VERSION 5.7 ;
  NOWIREEXTENSIONATPIN ON ;
  DIVIDERCHAR "/" ;
  BUSBITCHARS "[]" ;
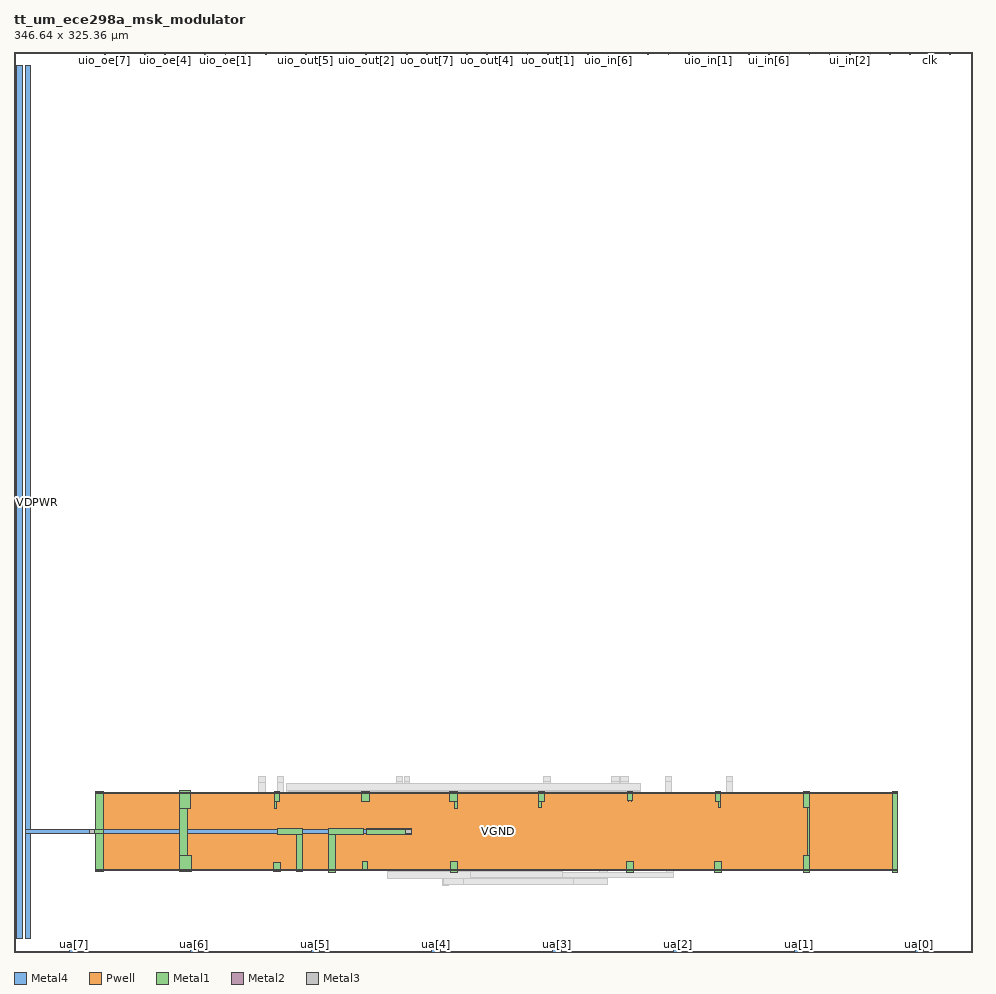
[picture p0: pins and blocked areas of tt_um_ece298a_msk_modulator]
MACRO tt_um_ece298a_msk_modulator
  CLASS BLOCK ;
  FOREIGN tt_um_ece298a_msk_modulator ;
  ORIGIN 0.000 0.000 ;
  SIZE 346.640 BY 325.360 ;
  PIN clk
    DIRECTION INPUT ;
    USE SIGNAL ;
    PORT
      LAYER Metal4 ;
        RECT 331.090 324.360 331.390 325.360 ;
    END
  END clk
  PIN ena
    DIRECTION INPUT ;
    USE SIGNAL ;
    PORT
      LAYER Metal4 ;
        RECT 338.370 324.360 338.670 325.360 ;
    END
  END ena
  PIN rst_n
    DIRECTION INPUT ;
    USE SIGNAL ;
    PORT
      LAYER Metal4 ;
        RECT 323.810 324.360 324.110 325.360 ;
    END
  END rst_n
  PIN ua[0]
    DIRECTION INOUT ;
    USE SIGNAL ;
    PORT
      LAYER Metal4 ;
        RECT 325.820 0.000 328.820 1.000 ;
    END
  END ua[0]
  PIN ua[1]
    DIRECTION INOUT ;
    USE SIGNAL ;
    PORT
      LAYER Metal4 ;
        RECT 282.140 0.000 285.140 1.000 ;
    END
  END ua[1]
  PIN ua[2]
    DIRECTION INOUT ;
    USE SIGNAL ;
    PORT
      LAYER Metal4 ;
        RECT 238.460 0.000 241.460 1.000 ;
    END
  END ua[2]
  PIN ua[3]
    DIRECTION INOUT ;
    USE SIGNAL ;
    PORT
      LAYER Metal4 ;
        RECT 194.780 0.000 197.780 1.000 ;
    END
  END ua[3]
  PIN ua[4]
    DIRECTION INOUT ;
    USE SIGNAL ;
    PORT
      LAYER Metal4 ;
        RECT 151.100 0.000 154.100 1.000 ;
    END
  END ua[4]
  PIN ua[5]
    DIRECTION INOUT ;
    USE SIGNAL ;
    PORT
      LAYER Metal4 ;
        RECT 107.420 0.000 110.420 1.000 ;
    END
  END ua[5]
  PIN ua[6]
    DIRECTION INOUT ;
    USE SIGNAL ;
    PORT
      LAYER Metal4 ;
        RECT 63.740 0.000 66.740 1.000 ;
    END
  END ua[6]
  PIN ua[7]
    DIRECTION INOUT ;
    USE SIGNAL ;
    PORT
      LAYER Metal4 ;
        RECT 20.060 0.000 23.060 1.000 ;
    END
  END ua[7]
  PIN ui_in[0]
    DIRECTION INPUT ;
    USE SIGNAL ;
    PORT
      LAYER Metal4 ;
        RECT 316.530 324.360 316.830 325.360 ;
    END
  END ui_in[0]
  PIN ui_in[1]
    DIRECTION INPUT ;
    USE SIGNAL ;
    PORT
      LAYER Metal4 ;
        RECT 309.250 324.360 309.550 325.360 ;
    END
  END ui_in[1]
  PIN ui_in[2]
    DIRECTION INPUT ;
    USE SIGNAL ;
    PORT
      LAYER Metal4 ;
        RECT 301.970 324.360 302.270 325.360 ;
    END
  END ui_in[2]
  PIN ui_in[3]
    DIRECTION INPUT ;
    USE SIGNAL ;
    PORT
      LAYER Metal4 ;
        RECT 294.690 324.360 294.990 325.360 ;
    END
  END ui_in[3]
  PIN ui_in[4]
    DIRECTION INPUT ;
    USE SIGNAL ;
    PORT
      LAYER Metal4 ;
        RECT 287.410 324.360 287.710 325.360 ;
    END
  END ui_in[4]
  PIN ui_in[5]
    DIRECTION INPUT ;
    USE SIGNAL ;
    PORT
      LAYER Metal4 ;
        RECT 280.130 324.360 280.430 325.360 ;
    END
  END ui_in[5]
  PIN ui_in[6]
    DIRECTION INPUT ;
    USE SIGNAL ;
    PORT
      LAYER Metal4 ;
        RECT 272.850 324.360 273.150 325.360 ;
    END
  END ui_in[6]
  PIN ui_in[7]
    DIRECTION INPUT ;
    USE SIGNAL ;
    PORT
      LAYER Metal4 ;
        RECT 265.570 324.360 265.870 325.360 ;
    END
  END ui_in[7]
  PIN uio_in[0]
    DIRECTION INPUT ;
    USE SIGNAL ;
    PORT
      LAYER Metal4 ;
        RECT 258.290 324.360 258.590 325.360 ;
    END
  END uio_in[0]
  PIN uio_in[1]
    DIRECTION INPUT ;
    USE SIGNAL ;
    PORT
      LAYER Metal4 ;
        RECT 251.010 324.360 251.310 325.360 ;
    END
  END uio_in[1]
  PIN uio_in[2]
    DIRECTION INPUT ;
    USE SIGNAL ;
    PORT
      LAYER Metal4 ;
        RECT 243.730 324.360 244.030 325.360 ;
    END
  END uio_in[2]
  PIN uio_in[3]
    DIRECTION INPUT ;
    USE SIGNAL ;
    PORT
      LAYER Metal4 ;
        RECT 236.450 324.360 236.750 325.360 ;
    END
  END uio_in[3]
  PIN uio_in[4]
    DIRECTION INPUT ;
    USE SIGNAL ;
    PORT
      LAYER Metal4 ;
        RECT 229.170 324.360 229.470 325.360 ;
    END
  END uio_in[4]
  PIN uio_in[5]
    DIRECTION INPUT ;
    USE SIGNAL ;
    PORT
      LAYER Metal4 ;
        RECT 221.890 324.360 222.190 325.360 ;
    END
  END uio_in[5]
  PIN uio_in[6]
    DIRECTION INPUT ;
    USE SIGNAL ;
    PORT
      LAYER Metal4 ;
        RECT 214.610 324.360 214.910 325.360 ;
    END
  END uio_in[6]
  PIN uio_in[7]
    DIRECTION INPUT ;
    USE SIGNAL ;
    PORT
      LAYER Metal4 ;
        RECT 207.330 324.360 207.630 325.360 ;
    END
  END uio_in[7]
  PIN uio_oe[0]
    DIRECTION OUTPUT ;
    USE SIGNAL ;
    PORT
      LAYER Metal4 ;
        RECT 83.570 324.360 83.870 325.360 ;
    END
  END uio_oe[0]
  PIN uio_oe[1]
    DIRECTION OUTPUT ;
    USE SIGNAL ;
    PORT
      LAYER Metal4 ;
        RECT 76.290 324.360 76.590 325.360 ;
    END
  END uio_oe[1]
  PIN uio_oe[2]
    DIRECTION OUTPUT ;
    USE SIGNAL ;
    PORT
      LAYER Metal4 ;
        RECT 69.010 324.360 69.310 325.360 ;
    END
  END uio_oe[2]
  PIN uio_oe[3]
    DIRECTION OUTPUT ;
    USE SIGNAL ;
    PORT
      LAYER Metal4 ;
        RECT 61.730 324.360 62.030 325.360 ;
    END
  END uio_oe[3]
  PIN uio_oe[4]
    DIRECTION OUTPUT ;
    USE SIGNAL ;
    PORT
      LAYER Metal4 ;
        RECT 54.450 324.360 54.750 325.360 ;
    END
  END uio_oe[4]
  PIN uio_oe[5]
    DIRECTION OUTPUT ;
    USE SIGNAL ;
    PORT
      LAYER Metal4 ;
        RECT 47.170 324.360 47.470 325.360 ;
    END
  END uio_oe[5]
  PIN uio_oe[6]
    DIRECTION OUTPUT ;
    USE SIGNAL ;
    PORT
      LAYER Metal4 ;
        RECT 39.890 324.360 40.190 325.360 ;
    END
  END uio_oe[6]
  PIN uio_oe[7]
    DIRECTION OUTPUT ;
    USE SIGNAL ;
    PORT
      LAYER Metal4 ;
        RECT 32.610 324.360 32.910 325.360 ;
    END
  END uio_oe[7]
  PIN uio_out[0]
    DIRECTION OUTPUT ;
    USE SIGNAL ;
    PORT
      LAYER Metal4 ;
        RECT 141.810 324.360 142.110 325.360 ;
    END
  END uio_out[0]
  PIN uio_out[1]
    DIRECTION OUTPUT ;
    USE SIGNAL ;
    PORT
      LAYER Metal4 ;
        RECT 134.530 324.360 134.830 325.360 ;
    END
  END uio_out[1]
  PIN uio_out[2]
    DIRECTION OUTPUT ;
    USE SIGNAL ;
    PORT
      LAYER Metal4 ;
        RECT 127.250 324.360 127.550 325.360 ;
    END
  END uio_out[2]
  PIN uio_out[3]
    DIRECTION OUTPUT ;
    USE SIGNAL ;
    PORT
      LAYER Metal4 ;
        RECT 119.970 324.360 120.270 325.360 ;
    END
  END uio_out[3]
  PIN uio_out[4]
    DIRECTION OUTPUT ;
    USE SIGNAL ;
    PORT
      LAYER Metal4 ;
        RECT 112.690 324.360 112.990 325.360 ;
    END
  END uio_out[4]
  PIN uio_out[5]
    DIRECTION OUTPUT ;
    USE SIGNAL ;
    PORT
      LAYER Metal4 ;
        RECT 105.410 324.360 105.710 325.360 ;
    END
  END uio_out[5]
  PIN uio_out[6]
    DIRECTION OUTPUT ;
    USE SIGNAL ;
    PORT
      LAYER Metal4 ;
        RECT 98.130 324.360 98.430 325.360 ;
    END
  END uio_out[6]
  PIN uio_out[7]
    DIRECTION OUTPUT ;
    USE SIGNAL ;
    PORT
      LAYER Metal4 ;
        RECT 90.850 324.360 91.150 325.360 ;
    END
  END uio_out[7]
  PIN uo_out[0]
    DIRECTION OUTPUT ;
    USE SIGNAL ;
    PORT
      LAYER Metal4 ;
        RECT 200.050 324.360 200.350 325.360 ;
    END
  END uo_out[0]
  PIN uo_out[1]
    DIRECTION OUTPUT ;
    USE SIGNAL ;
    PORT
      LAYER Metal4 ;
        RECT 192.770 324.360 193.070 325.360 ;
    END
  END uo_out[1]
  PIN uo_out[2]
    DIRECTION OUTPUT ;
    USE SIGNAL ;
    PORT
      LAYER Metal4 ;
        RECT 185.490 324.360 185.790 325.360 ;
    END
  END uo_out[2]
  PIN uo_out[3]
    DIRECTION OUTPUT ;
    USE SIGNAL ;
    PORT
      LAYER Metal4 ;
        RECT 178.210 324.360 178.510 325.360 ;
    END
  END uo_out[3]
  PIN uo_out[4]
    DIRECTION OUTPUT ;
    USE SIGNAL ;
    PORT
      LAYER Metal4 ;
        RECT 170.930 324.360 171.230 325.360 ;
    END
  END uo_out[4]
  PIN uo_out[5]
    DIRECTION OUTPUT ;
    USE SIGNAL ;
    PORT
      LAYER Metal4 ;
        RECT 163.650 324.360 163.950 325.360 ;
    END
  END uo_out[5]
  PIN uo_out[6]
    DIRECTION OUTPUT ;
    USE SIGNAL ;
    PORT
      LAYER Metal4 ;
        RECT 156.370 324.360 156.670 325.360 ;
    END
  END uo_out[6]
  PIN uo_out[7]
    DIRECTION OUTPUT ;
    USE SIGNAL ;
    PORT
      LAYER Metal4 ;
        RECT 149.090 324.360 149.390 325.360 ;
    END
  END uo_out[7]
  PIN VDPWR
    DIRECTION INOUT ;
    USE POWER ;
    PORT
      LAYER Metal4 ;
        RECT 1.000 5.000 3.000 320.360 ;
    END
  END VDPWR
  PIN VGND
    DIRECTION INOUT ;
    USE GROUND ;
    PORT
      LAYER Pwell ;
        RECT 30.350 29.350 319.290 57.710 ;
      LAYER Metal1 ;
        RECT 29.600 57.525 32.350 57.950 ;
        RECT 60.000 57.525 63.900 58.250 ;
        RECT 94.000 57.525 95.850 58.050 ;
        RECT 125.500 57.525 128.450 57.950 ;
        RECT 157.550 57.525 160.500 57.950 ;
        RECT 189.450 57.525 191.750 58.100 ;
        RECT 221.800 57.525 223.750 58.100 ;
        RECT 253.600 57.525 255.550 57.950 ;
        RECT 285.500 57.525 287.750 58.050 ;
        RECT 317.450 57.525 319.450 58.100 ;
        RECT 29.600 57.295 319.450 57.525 ;
        RECT 29.600 44.400 32.350 57.295 ;
        RECT 27.200 42.700 32.350 44.400 ;
        RECT 29.600 29.765 32.350 42.700 ;
        RECT 60.000 52.050 63.900 57.295 ;
        RECT 94.000 54.400 95.850 57.295 ;
        RECT 125.500 54.500 128.450 57.295 ;
        RECT 157.550 54.500 160.500 57.295 ;
        RECT 94.000 52.050 94.850 54.400 ;
        RECT 159.200 52.050 160.500 54.500 ;
        RECT 189.450 54.500 191.750 57.295 ;
        RECT 221.800 54.600 223.750 57.295 ;
        RECT 222.055 54.540 222.285 54.600 ;
        RECT 223.115 54.540 223.345 54.600 ;
        RECT 189.450 52.100 190.600 54.500 ;
        RECT 253.600 54.450 255.550 57.295 ;
        RECT 254.800 52.100 255.500 54.450 ;
        RECT 285.500 52.100 287.750 57.295 ;
        RECT 60.000 34.950 62.750 52.050 ;
        RECT 95.400 42.550 104.300 44.550 ;
        RECT 95.435 42.540 95.665 42.550 ;
        RECT 60.000 29.765 64.250 34.950 ;
        RECT 94.375 32.500 94.605 32.520 ;
        RECT 95.435 32.500 95.665 32.520 ;
        RECT 93.900 29.765 96.200 32.500 ;
        RECT 102.300 29.765 104.300 42.550 ;
        RECT 113.600 44.500 116.050 44.550 ;
        RECT 126.295 44.500 126.525 44.520 ;
        RECT 113.600 42.550 126.525 44.500 ;
        RECT 113.600 29.765 116.050 42.550 ;
        RECT 126.295 42.540 126.525 42.550 ;
        RECT 127.355 44.500 127.585 44.520 ;
        RECT 127.355 42.600 143.700 44.500 ;
        RECT 127.355 42.540 127.585 42.600 ;
        RECT 285.895 34.900 286.125 34.920 ;
        RECT 286.750 34.900 287.750 52.100 ;
        RECT 126.050 29.765 127.900 32.600 ;
        RECT 157.750 29.765 160.150 32.600 ;
        RECT 221.550 29.765 223.950 32.650 ;
        RECT 253.400 29.765 255.800 32.600 ;
        RECT 285.350 29.765 287.750 34.900 ;
        RECT 317.450 29.765 319.450 57.295 ;
        RECT 29.600 29.535 319.450 29.765 ;
        RECT 29.600 29.000 32.350 29.535 ;
        RECT 60.000 29.150 64.250 29.535 ;
        RECT 93.900 29.200 96.200 29.535 ;
        RECT 102.300 29.050 104.300 29.535 ;
        RECT 113.600 28.900 116.050 29.535 ;
        RECT 126.050 29.400 127.900 29.535 ;
        RECT 157.750 28.900 160.150 29.535 ;
        RECT 221.550 28.850 223.950 29.535 ;
        RECT 253.400 28.800 255.800 29.535 ;
        RECT 285.350 28.900 287.750 29.535 ;
        RECT 317.450 28.900 319.450 29.535 ;
      LAYER Metal2 ;
        RECT 27.200 42.700 29.200 44.350 ;
        RECT 141.600 42.700 143.550 44.400 ;
      LAYER Metal3 ;
        RECT 27.200 42.700 29.200 44.350 ;
        RECT 141.600 42.700 143.550 44.400 ;
      LAYER Metal4 ;
        RECT 4.000 44.400 6.000 320.360 ;
        RECT 4.000 44.365 27.450 44.400 ;
        RECT 126.900 44.365 143.600 44.400 ;
        RECT 4.000 42.700 143.600 44.365 ;
        RECT 4.000 5.000 6.000 42.700 ;
    END
  END VGND
  OBS
      LAYER Metal1 ;
        RECT 95.435 54.100 95.665 54.120 ;
        RECT 95.400 52.200 112.150 54.100 ;
        RECT 95.435 52.140 95.665 52.200 ;
        RECT 63.450 49.700 67.700 51.800 ;
        RECT 84.750 49.650 94.650 51.800 ;
        RECT 95.250 49.750 107.750 51.750 ;
        RECT 95.435 49.740 95.665 49.750 ;
        RECT 63.515 49.300 63.745 49.320 ;
        RECT 94.375 49.300 94.605 49.320 ;
        RECT 95.435 49.300 95.665 49.320 ;
        RECT 63.500 47.300 91.050 49.300 ;
        RECT 91.500 47.200 94.750 49.300 ;
        RECT 95.200 47.350 97.250 49.300 ;
        RECT 95.435 47.340 95.665 47.350 ;
        RECT 63.515 46.900 63.745 46.920 ;
        RECT 94.375 46.900 94.605 46.920 ;
        RECT 63.400 42.450 65.250 46.900 ;
        RECT 91.600 44.940 94.605 46.900 ;
        RECT 95.150 45.000 97.250 46.950 ;
        RECT 95.435 44.940 95.665 45.000 ;
        RECT 91.600 44.850 94.600 44.940 ;
        RECT 94.375 44.500 94.605 44.520 ;
        RECT 91.950 42.600 94.750 44.500 ;
        RECT 94.375 42.540 94.605 42.600 ;
        RECT 63.350 37.700 65.200 42.150 ;
        RECT 92.100 42.120 94.550 42.150 ;
        RECT 92.100 40.140 94.605 42.120 ;
        RECT 95.435 42.100 95.665 42.120 ;
        RECT 95.100 40.150 97.200 42.100 ;
        RECT 95.435 40.140 95.665 40.150 ;
        RECT 92.100 40.100 94.550 40.140 ;
        RECT 92.100 39.720 94.600 39.750 ;
        RECT 92.100 37.740 94.605 39.720 ;
        RECT 92.100 37.700 94.600 37.740 ;
        RECT 95.100 37.350 97.000 39.750 ;
        RECT 63.300 35.300 91.600 37.350 ;
        RECT 94.000 35.300 97.100 37.350 ;
        RECT 108.950 35.550 112.150 52.200 ;
        RECT 125.950 52.100 127.950 54.150 ;
        RECT 132.150 52.200 158.750 54.150 ;
        RECT 132.150 52.150 136.200 52.200 ;
        RECT 158.215 52.140 158.445 52.200 ;
        RECT 191.050 52.150 194.150 54.200 ;
        RECT 211.600 52.150 222.550 54.150 ;
        RECT 223.115 54.100 223.345 54.120 ;
        RECT 223.115 52.200 226.050 54.100 ;
        RECT 191.195 52.140 191.425 52.150 ;
        RECT 222.055 52.140 222.285 52.150 ;
        RECT 223.115 52.140 223.345 52.200 ;
        RECT 250.550 52.150 254.550 54.150 ;
        RECT 253.975 52.140 254.205 52.150 ;
        RECT 126.050 49.600 127.950 51.800 ;
        RECT 155.200 51.700 158.950 51.750 ;
        RECT 135.250 49.750 159.000 51.700 ;
        RECT 155.200 49.700 158.950 49.750 ;
        RECT 159.275 49.740 159.505 51.720 ;
        RECT 190.135 49.740 190.365 51.720 ;
        RECT 191.000 49.750 202.950 51.750 ;
        RECT 221.650 49.750 223.850 51.750 ;
        RECT 224.850 49.750 254.450 51.750 ;
        RECT 255.035 51.700 255.265 51.720 ;
        RECT 254.800 49.750 257.100 51.700 ;
        RECT 191.195 49.740 191.425 49.750 ;
        RECT 222.055 49.740 222.285 49.750 ;
        RECT 223.115 49.740 223.345 49.750 ;
        RECT 253.975 49.740 254.205 49.750 ;
        RECT 255.035 49.740 255.265 49.750 ;
        RECT 284.600 49.350 286.350 51.850 ;
        RECT 124.750 47.350 126.600 49.350 ;
        RECT 127.355 49.300 127.585 49.320 ;
        RECT 126.295 47.340 126.525 47.350 ;
        RECT 127.355 47.340 147.950 49.300 ;
        RECT 148.650 47.350 160.150 49.350 ;
        RECT 190.135 49.300 190.365 49.320 ;
        RECT 158.215 47.340 158.445 47.350 ;
        RECT 159.275 47.340 159.505 47.350 ;
        RECT 127.400 47.300 147.950 47.340 ;
        RECT 186.350 47.300 190.450 49.300 ;
        RECT 191.150 47.250 193.600 49.350 ;
        RECT 222.055 49.300 222.285 49.320 ;
        RECT 223.115 49.300 223.345 49.320 ;
        RECT 221.700 47.300 225.500 49.300 ;
        RECT 227.000 47.350 254.500 49.350 ;
        RECT 253.975 47.340 254.205 47.350 ;
        RECT 254.900 47.300 257.100 49.350 ;
        RECT 124.700 44.950 126.700 47.000 ;
        RECT 127.450 46.920 143.150 47.000 ;
        RECT 127.355 44.950 143.150 46.920 ;
        RECT 155.550 44.950 158.850 46.950 ;
        RECT 159.275 46.900 159.505 46.920 ;
        RECT 126.295 44.940 126.525 44.950 ;
        RECT 127.355 44.940 127.585 44.950 ;
        RECT 158.215 44.940 158.445 44.950 ;
        RECT 159.150 44.850 161.550 46.900 ;
        RECT 162.250 45.000 190.500 46.950 ;
        RECT 190.135 44.940 190.365 45.000 ;
        RECT 191.005 44.915 195.760 46.940 ;
        RECT 158.215 44.475 158.445 44.520 ;
        RECT 159.275 44.475 159.505 44.520 ;
        RECT 190.135 44.475 190.365 44.520 ;
        RECT 191.195 44.475 191.425 44.520 ;
        RECT 157.905 42.545 191.670 44.475 ;
        RECT 220.900 42.545 222.515 47.025 ;
        RECT 223.200 46.920 225.500 47.300 ;
        RECT 283.150 47.250 286.350 49.350 ;
        RECT 223.115 44.940 225.500 46.920 ;
        RECT 229.950 44.950 254.500 46.950 ;
        RECT 253.975 44.940 254.205 44.950 ;
        RECT 223.200 44.900 225.500 44.940 ;
        RECT 254.950 44.900 257.200 47.000 ;
        RECT 257.700 44.900 286.300 46.950 ;
        RECT 223.150 44.520 255.700 44.600 ;
        RECT 158.215 42.540 158.445 42.545 ;
        RECT 159.275 42.540 159.505 42.545 ;
        RECT 190.135 42.540 190.365 42.545 ;
        RECT 191.195 42.540 191.425 42.545 ;
        RECT 222.055 42.540 222.285 42.545 ;
        RECT 223.115 42.540 255.700 44.520 ;
        RECT 223.150 42.500 255.700 42.540 ;
        RECT 280.950 42.500 286.350 44.550 ;
        RECT 223.150 42.450 245.400 42.500 ;
        RECT 126.295 42.100 126.525 42.120 ;
        RECT 127.355 42.100 127.585 42.120 ;
        RECT 124.800 40.100 126.750 42.100 ;
        RECT 127.355 40.140 153.500 42.100 ;
        RECT 158.215 42.080 158.445 42.120 ;
        RECT 159.275 42.100 159.505 42.120 ;
        RECT 156.015 40.155 158.855 42.080 ;
        RECT 159.150 42.050 162.950 42.100 ;
        RECT 190.135 42.050 190.365 42.120 ;
        RECT 191.195 42.050 191.425 42.120 ;
        RECT 159.150 40.200 164.700 42.050 ;
        RECT 158.215 40.140 158.445 40.155 ;
        RECT 159.275 40.140 159.505 40.200 ;
        RECT 127.500 40.100 153.500 40.140 ;
        RECT 189.100 40.100 192.450 42.050 ;
        RECT 196.650 40.100 222.600 42.200 ;
        RECT 223.000 40.050 234.850 42.150 ;
        RECT 235.400 40.050 254.300 42.150 ;
        RECT 255.000 40.100 256.850 42.150 ;
        RECT 285.895 42.100 286.125 42.120 ;
        RECT 148.700 39.720 158.350 39.750 ;
        RECT 159.400 39.720 160.900 39.750 ;
        RECT 126.295 39.700 126.525 39.720 ;
        RECT 127.355 39.700 127.585 39.720 ;
        RECT 124.750 37.650 126.650 39.700 ;
        RECT 127.355 37.800 148.200 39.700 ;
        RECT 127.355 37.740 127.585 37.800 ;
        RECT 148.700 37.750 158.445 39.720 ;
        RECT 158.215 37.740 158.445 37.750 ;
        RECT 159.275 37.850 160.900 39.720 ;
        RECT 186.400 39.720 190.250 39.750 ;
        RECT 159.275 37.740 159.505 37.850 ;
        RECT 186.400 37.750 190.365 39.720 ;
        RECT 190.135 37.740 190.365 37.750 ;
        RECT 190.950 37.700 192.600 39.750 ;
        RECT 221.700 37.700 223.700 39.750 ;
        RECT 224.650 37.650 254.250 39.800 ;
        RECT 255.000 37.750 261.500 39.800 ;
        RECT 255.035 37.740 255.265 37.750 ;
        RECT 284.700 37.700 286.400 42.100 ;
        RECT 94.375 32.940 94.605 34.920 ;
        RECT 95.100 32.900 102.000 34.950 ;
        RECT 108.900 32.750 112.200 35.550 ;
        RECT 122.050 35.300 126.650 37.350 ;
        RECT 127.300 35.350 140.450 37.400 ;
        RECT 127.355 35.340 127.585 35.350 ;
        RECT 156.400 35.300 158.650 37.350 ;
        RECT 159.275 35.340 159.505 37.320 ;
        RECT 190.135 35.340 190.365 37.320 ;
        RECT 191.000 35.400 198.200 37.350 ;
        RECT 222.055 37.250 222.285 37.320 ;
        RECT 191.195 35.340 191.425 35.400 ;
        RECT 216.000 35.350 222.550 37.250 ;
        RECT 222.055 35.340 222.285 35.350 ;
        RECT 223.000 35.300 238.400 37.350 ;
        RECT 253.600 37.300 255.700 37.400 ;
        RECT 252.400 37.250 255.700 37.300 ;
        RECT 252.400 35.300 264.750 37.250 ;
        RECT 283.450 35.300 286.400 37.400 ;
        RECT 225.100 35.000 227.300 35.050 ;
        RECT 154.950 34.920 158.400 34.950 ;
        RECT 219.300 34.920 222.200 34.950 ;
        RECT 126.295 34.900 126.525 34.920 ;
        RECT 127.355 34.900 127.585 34.920 ;
        RECT 125.950 32.850 127.950 34.900 ;
        RECT 154.950 32.940 158.445 34.920 ;
        RECT 159.275 32.940 159.505 34.920 ;
        RECT 190.135 32.940 190.365 34.920 ;
        RECT 191.195 34.900 191.425 34.920 ;
        RECT 191.195 32.940 194.800 34.900 ;
        RECT 219.300 32.950 222.285 34.920 ;
        RECT 222.055 32.940 222.285 32.950 ;
        RECT 154.950 32.900 158.400 32.940 ;
        RECT 191.200 32.850 194.800 32.940 ;
        RECT 222.600 32.900 227.300 35.000 ;
        RECT 190.135 30.540 190.365 32.520 ;
        RECT 191.195 30.540 191.425 32.520 ;
        RECT 225.100 30.300 227.300 32.900 ;
        RECT 252.400 32.850 254.800 35.300 ;
        RECT 255.035 32.940 255.265 34.920 ;
      LAYER Metal2 ;
        RECT 65.650 46.850 67.550 51.700 ;
        RECT 63.450 45.000 67.550 46.850 ;
        RECT 84.700 40.150 87.050 51.800 ;
        RECT 88.550 47.300 91.000 63.400 ;
        RECT 91.500 47.200 94.750 49.300 ;
        RECT 95.200 47.350 97.250 63.400 ;
        RECT 91.600 44.850 94.600 46.900 ;
        RECT 91.950 42.600 94.750 44.500 ;
        RECT 92.100 40.100 94.550 42.150 ;
        RECT 95.100 40.150 97.250 46.900 ;
        RECT 92.100 37.700 94.600 39.750 ;
        RECT 88.450 35.350 91.750 37.350 ;
        RECT 98.450 32.900 102.100 61.050 ;
        RECT 104.850 29.900 107.750 51.650 ;
        RECT 108.600 47.250 111.800 57.300 ;
        RECT 112.700 46.750 114.950 54.100 ;
        RECT 112.600 44.900 114.950 46.750 ;
        RECT 115.600 40.100 118.250 51.700 ;
        RECT 118.650 35.300 121.600 51.800 ;
        RECT 122.050 35.300 124.300 49.300 ;
        RECT 124.750 47.350 126.600 49.350 ;
        RECT 124.700 44.950 126.700 47.000 ;
        RECT 124.800 40.100 126.750 42.100 ;
        RECT 124.750 37.650 126.650 39.700 ;
        RECT 128.900 35.350 131.450 44.500 ;
        RECT 108.950 32.750 112.200 34.950 ;
        RECT 132.500 29.800 134.650 54.150 ;
        RECT 135.150 26.750 137.800 51.850 ;
        RECT 138.250 35.300 140.400 63.400 ;
        RECT 141.050 44.950 143.100 63.400 ;
        RECT 191.250 52.250 194.050 63.400 ;
        RECT 143.550 47.350 145.400 51.700 ;
        RECT 145.850 47.300 148.050 49.350 ;
        RECT 143.950 42.500 145.950 46.950 ;
        RECT 146.300 39.750 148.350 46.950 ;
        RECT 146.250 37.850 148.350 39.750 ;
        RECT 146.250 37.800 148.300 37.850 ;
        RECT 148.700 37.750 150.450 49.350 ;
        RECT 155.450 46.900 157.900 46.950 ;
        RECT 150.750 40.100 153.500 46.850 ;
        RECT 155.450 44.850 157.950 46.900 ;
        RECT 159.150 44.850 161.550 46.900 ;
        RECT 155.450 44.500 157.900 44.850 ;
        RECT 155.450 42.550 157.950 44.500 ;
        RECT 156.015 40.155 158.855 42.080 ;
        RECT 162.250 40.200 164.650 46.950 ;
        RECT 165.200 44.900 167.300 51.750 ;
        RECT 150.850 37.900 153.500 40.100 ;
        RECT 159.100 37.850 160.900 39.750 ;
        RECT 156.400 37.300 158.650 37.350 ;
        RECT 161.450 37.300 163.450 39.700 ;
        RECT 156.400 35.450 163.450 37.300 ;
        RECT 156.400 35.350 163.400 35.450 ;
        RECT 156.400 35.300 158.650 35.350 ;
        RECT 180.600 35.200 182.900 39.750 ;
        RECT 183.600 37.650 185.550 49.350 ;
        RECT 186.400 37.750 188.450 49.300 ;
        RECT 188.850 47.350 190.800 51.700 ;
        RECT 191.150 47.250 193.600 49.350 ;
        RECT 194.350 47.350 196.550 51.750 ;
        RECT 193.315 44.800 195.770 46.940 ;
        RECT 193.315 40.155 195.740 44.800 ;
        RECT 196.650 40.100 199.100 44.450 ;
        RECT 190.950 37.700 192.600 39.750 ;
        RECT 155.000 24.200 157.250 34.900 ;
        RECT 191.200 32.850 194.800 34.900 ;
        RECT 192.400 27.050 194.700 32.850 ;
        RECT 195.900 24.400 198.250 37.350 ;
        RECT 200.250 35.250 202.950 51.700 ;
        RECT 211.650 24.450 214.550 54.000 ;
        RECT 216.000 35.350 218.750 63.400 ;
        RECT 219.300 34.950 222.100 63.400 ;
        RECT 223.300 52.200 226.050 61.000 ;
        RECT 224.850 47.400 226.500 51.700 ;
        RECT 229.850 49.650 232.000 54.150 ;
        RECT 224.650 37.700 226.450 46.900 ;
        RECT 227.050 37.800 229.000 49.300 ;
        RECT 229.850 47.350 232.050 49.650 ;
        RECT 229.950 40.100 231.850 46.950 ;
        RECT 232.750 44.950 234.950 54.150 ;
        RECT 232.250 40.200 234.750 44.600 ;
        RECT 235.400 40.050 237.750 63.400 ;
        RECT 239.600 37.650 241.900 49.200 ;
        RECT 219.300 32.950 222.200 34.950 ;
        RECT 225.000 30.150 227.350 32.350 ;
        RECT 235.900 28.900 238.350 37.350 ;
        RECT 242.250 35.300 244.900 44.600 ;
        RECT 246.050 42.600 249.300 57.150 ;
        RECT 250.550 52.150 254.550 54.150 ;
        RECT 254.800 49.750 257.100 51.700 ;
        RECT 254.900 47.300 257.100 49.350 ;
        RECT 254.950 44.900 257.200 47.000 ;
        RECT 257.700 44.900 259.700 63.400 ;
        RECT 255.000 40.100 256.850 42.150 ;
        RECT 258.450 37.800 261.400 44.400 ;
        RECT 262.450 35.400 264.750 54.050 ;
        RECT 280.900 47.300 286.350 49.350 ;
        RECT 280.950 42.500 283.550 47.300 ;
        RECT 283.450 35.150 286.400 37.400 ;
        RECT 235.900 27.000 238.450 28.900 ;
      LAYER Metal3 ;
        RECT 88.550 61.400 91.000 63.450 ;
        RECT 95.200 61.450 97.250 63.400 ;
        RECT 138.250 61.800 140.400 63.500 ;
        RECT 141.100 61.650 143.100 63.450 ;
        RECT 191.250 61.500 194.050 63.400 ;
        RECT 216.000 61.650 218.750 63.600 ;
        RECT 219.300 61.650 222.200 63.400 ;
        RECT 235.400 61.700 237.750 63.550 ;
        RECT 257.700 61.700 259.650 63.400 ;
        RECT 98.550 61.000 102.800 61.050 ;
        RECT 98.550 58.250 226.350 61.000 ;
        RECT 99.150 58.200 226.350 58.250 ;
        RECT 108.700 54.550 249.300 57.300 ;
        RECT 109.700 54.450 249.300 54.550 ;
        RECT 112.650 52.200 232.050 54.150 ;
        RECT 250.550 54.100 260.650 54.150 ;
        RECT 217.650 52.150 232.050 52.200 ;
        RECT 232.800 52.150 235.000 54.100 ;
        RECT 250.550 54.050 262.250 54.100 ;
        RECT 250.550 52.150 264.800 54.050 ;
        RECT 252.150 52.100 264.800 52.150 ;
        RECT 115.600 49.700 118.250 51.700 ;
        RECT 118.750 49.650 142.900 51.800 ;
        RECT 143.550 51.700 145.450 51.750 ;
        RECT 143.550 49.700 167.250 51.700 ;
        RECT 188.900 49.750 196.550 51.800 ;
        RECT 196.950 49.750 257.100 51.700 ;
        RECT 91.500 47.250 112.100 49.300 ;
        RECT 122.000 47.300 124.350 49.350 ;
        RECT 124.750 47.350 145.500 49.300 ;
        RECT 145.850 47.300 185.500 49.350 ;
        RECT 188.850 47.350 190.750 49.350 ;
        RECT 191.150 47.250 193.600 49.350 ;
        RECT 194.350 47.350 226.800 49.350 ;
        RECT 229.850 47.350 237.900 49.350 ;
        RECT 239.450 47.350 257.050 49.400 ;
        RECT 91.850 46.700 114.950 46.900 ;
        RECT 91.800 45.050 114.950 46.700 ;
        RECT 91.850 44.900 114.950 45.050 ;
        RECT 124.700 44.950 145.950 47.000 ;
        RECT 150.750 46.900 160.700 46.950 ;
        RECT 146.300 44.850 148.350 46.900 ;
        RECT 150.750 44.850 161.550 46.900 ;
        RECT 165.200 44.950 226.600 46.900 ;
        RECT 232.750 44.950 257.200 46.950 ;
        RECT 161.800 44.550 199.200 44.650 ;
        RECT 91.950 42.600 131.550 44.500 ;
        RECT 144.000 42.600 154.650 44.550 ;
        RECT 161.750 44.500 199.200 44.550 ;
        RECT 246.100 44.500 249.450 44.650 ;
        RECT 155.500 42.550 199.200 44.500 ;
        RECT 199.750 42.550 234.700 44.500 ;
        RECT 235.400 42.150 237.950 43.500 ;
        RECT 246.100 42.500 261.450 44.500 ;
        RECT 84.650 40.150 87.050 42.150 ;
        RECT 92.100 40.100 118.150 42.100 ;
        RECT 124.850 40.100 155.450 42.050 ;
        RECT 156.015 40.155 195.825 42.080 ;
        RECT 199.850 40.150 231.850 42.100 ;
        RECT 235.400 40.100 256.850 42.150 ;
        RECT 92.100 37.700 124.200 39.750 ;
        RECT 124.700 37.650 145.400 39.750 ;
        RECT 150.850 39.500 160.850 39.700 ;
        RECT 150.850 38.000 160.900 39.500 ;
        RECT 150.850 37.900 160.850 38.000 ;
        RECT 161.500 37.750 182.900 39.750 ;
        RECT 183.600 37.650 192.600 39.700 ;
        RECT 193.250 37.650 229.200 39.850 ;
        RECT 229.650 37.650 241.900 39.700 ;
        RECT 88.450 35.350 121.700 37.300 ;
        RECT 128.900 35.350 180.150 37.350 ;
        RECT 108.900 34.850 173.650 34.900 ;
        RECT 108.900 32.850 173.700 34.850 ;
        RECT 108.900 32.800 164.800 32.850 ;
        RECT 104.850 29.900 132.050 32.400 ;
        RECT 167.950 32.350 170.600 32.450 ;
        RECT 132.500 30.050 170.650 32.350 ;
        RECT 171.200 30.250 173.700 32.850 ;
        RECT 174.500 32.450 176.950 35.000 ;
        RECT 177.500 32.750 180.150 35.350 ;
        RECT 180.600 35.250 202.950 37.300 ;
        RECT 203.450 35.250 245.050 37.250 ;
        RECT 180.600 35.200 182.800 35.250 ;
        RECT 203.450 32.850 205.850 35.250 ;
        RECT 283.450 35.150 286.400 37.400 ;
        RECT 209.300 34.900 235.050 34.950 ;
        RECT 206.250 32.800 235.050 34.900 ;
        RECT 206.250 32.450 209.150 32.800 ;
        RECT 174.500 30.300 209.150 32.450 ;
        RECT 225.000 30.150 227.350 32.350 ;
        RECT 132.500 30.000 137.500 30.050 ;
        RECT 165.050 28.950 167.300 29.050 ;
        RECT 135.150 26.750 167.300 28.950 ;
        RECT 167.950 28.900 170.600 30.050 ;
        RECT 167.950 27.000 194.700 28.900 ;
        RECT 196.050 27.000 238.400 28.900 ;
        RECT 155.100 24.350 164.450 26.400 ;
        RECT 165.050 26.350 167.300 26.750 ;
        RECT 165.050 24.400 198.350 26.350 ;
        RECT 198.800 24.450 214.400 26.550 ;
      LAYER Metal4 ;
        RECT 88.550 61.400 91.000 63.450 ;
        RECT 95.200 61.450 97.250 63.400 ;
        RECT 138.250 61.800 140.400 63.500 ;
        RECT 141.100 61.650 143.100 63.450 ;
        RECT 191.250 61.500 194.050 63.400 ;
        RECT 216.000 61.650 218.750 63.600 ;
        RECT 219.300 61.650 222.200 63.400 ;
        RECT 235.400 61.700 237.750 63.550 ;
        RECT 257.700 61.700 259.650 63.400 ;
        RECT 137.650 52.100 234.700 54.150 ;
        RECT 137.650 51.700 140.050 52.100 ;
        RECT 115.600 49.700 140.050 51.700 ;
        RECT 196.950 51.650 199.900 51.700 ;
        RECT 140.350 49.750 199.900 51.650 ;
        RECT 122.050 47.350 190.750 49.350 ;
        RECT 191.200 46.900 193.450 49.300 ;
        RECT 146.300 44.850 193.650 46.900 ;
        RECT 152.200 44.350 202.250 44.550 ;
        RECT 152.200 42.600 202.300 44.350 ;
        RECT 152.200 42.500 202.250 42.600 ;
        RECT 235.400 42.250 237.950 49.350 ;
        RECT 235.600 42.200 237.850 42.250 ;
        RECT 84.700 40.150 121.450 42.150 ;
        RECT 153.650 40.150 202.500 42.100 ;
        RECT 118.850 34.900 121.450 40.150 ;
        RECT 122.050 37.250 124.450 39.750 ;
        RECT 143.300 37.650 195.400 39.700 ;
        RECT 229.800 37.300 232.150 39.700 ;
        RECT 140.650 37.250 232.150 37.300 ;
        RECT 122.050 35.250 232.150 37.250 ;
        RECT 232.550 35.200 286.400 37.400 ;
        RECT 118.850 32.800 177.000 34.900 ;
        RECT 177.500 34.850 180.300 34.950 ;
        RECT 177.500 32.900 205.900 34.850 ;
        RECT 177.500 32.750 180.300 32.900 ;
        RECT 232.550 32.850 234.900 35.200 ;
        RECT 129.250 29.900 167.750 32.400 ;
        RECT 171.200 30.300 227.350 32.400 ;
        RECT 165.050 29.000 167.700 29.900 ;
        RECT 165.050 27.000 198.150 29.000 ;
        RECT 162.350 24.350 202.100 26.500 ;
  END
END tt_um_ece298a_msk_modulator
END LIBRARY

